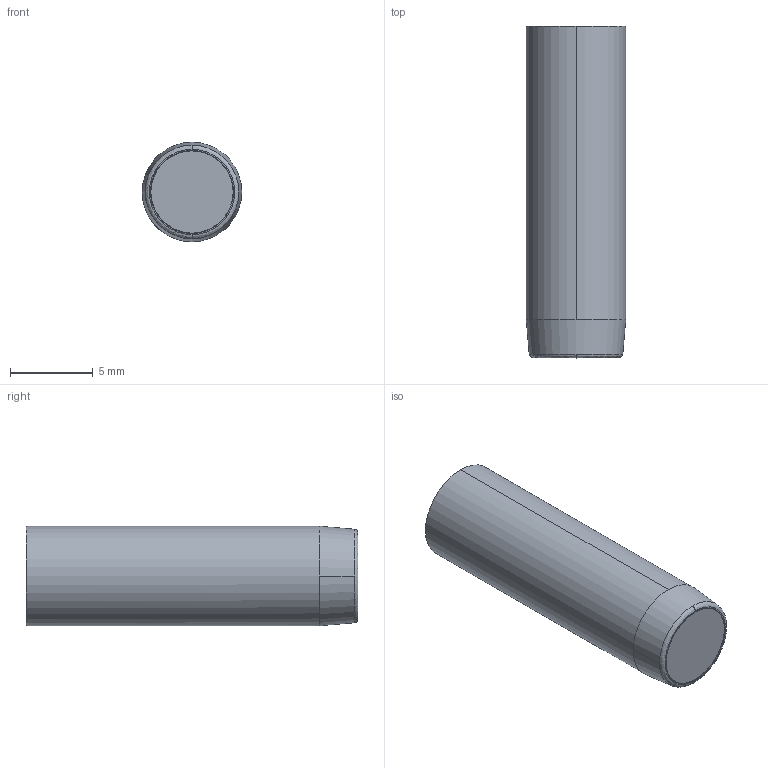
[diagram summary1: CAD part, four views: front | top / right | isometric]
IGES file: header records copied from the file, then geometry measured from it (millimetres).
Start section: START RECORD GO HERE.
Global section: file name: fa063212-21.igs; native system: DASSAULT SYSTEMES CATIA V5 R20 - www.3ds.com; preprocessor: CATIA Version 5 Release 20 ; author: Utente; organization: NB04-ASUS; date: 20201108.083821; units: millimetre
Bounding box: 6 x 20 x 6 mm (x, y, z)
Surface area: 1126.5 mm2 (no closed solid volume)
Topology: 0 solids, 0 shells, 438 faces, 2159 edges, 2157 vertices
Faces by surface type: revolution 176, plane 151, bspline 111
